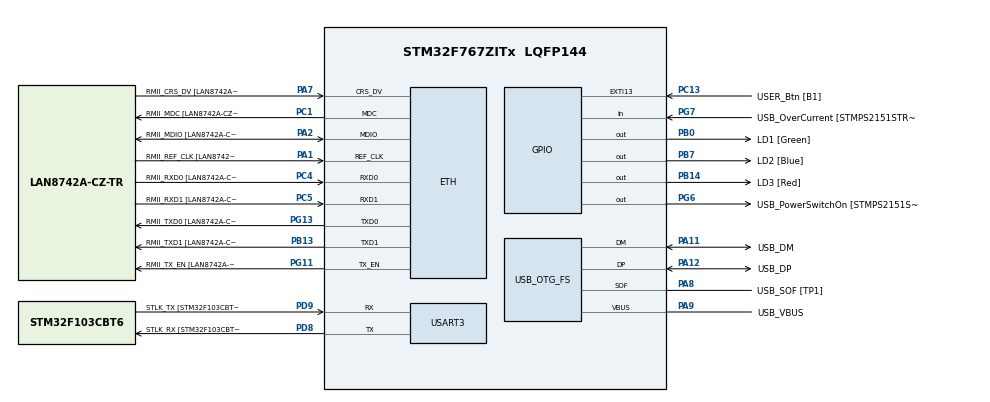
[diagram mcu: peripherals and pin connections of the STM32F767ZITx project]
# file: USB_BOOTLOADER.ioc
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ETH.MediaInterface=ETH_MEDIA_INTERFACE_RMII
ETH.PHY_Name=LAN8742A_PHY_ADDRESS
ETH.PHY_Value=0
ETH.PhyAddress=0
Mcu.Family=STM32F7
Mcu.Name=STM32F767ZITx
Mcu.Package=LQFP144
NVIC.OTG_FS_IRQn=true\:0\:0\:false\:false\:true\:true\:true
NVIC.PriorityGroup=NVIC_PRIORITYGROUP_4
PA1.GPIO_Label=RMII_REF_CLK [LAN8742A-CZ-TR_REFCLK0]
PA1.Mode=RMII
PA1.Signal=ETH_REF_CLK
PA10.GPIO_Label=USB_ID
PA10.Signal=USB_OTG_FS_ID
PA11.GPIO_Label=USB_DM
PA11.Mode=Host_Only
PA11.Signal=USB_OTG_FS_DM
PA12.GPIO_Label=USB_DP
PA12.Mode=Host_Only
PA12.Signal=USB_OTG_FS_DP
PA13.GPIO_Label=TMS
PA13.Mode=Serial_Wire
PA13.Signal=SYS_JTMS-SWDIO
PA14.GPIO_Label=TCK
PA14.Mode=Serial_Wire
PA14.Signal=SYS_JTCK-SWCLK
PA2.GPIO_Label=RMII_MDIO [LAN8742A-CZ-TR_MDIO]
PA2.Mode=RMII
PA2.Signal=ETH_MDIO
PA7.GPIO_Label=RMII_CRS_DV [LAN8742A-CZ-TR_CRS_DV]
PA7.Mode=RMII
PA7.Signal=ETH_CRS_DV
PA8.GPIO_Label=USB_SOF [TP1]
PA8.Mode=Activate_SOF_FS
PA8.Signal=USB_OTG_FS_SOF
PA9.GPIO_Label=USB_VBUS
PA9.Mode=Activate_VBUS
PA9.Signal=USB_OTG_FS_VBUS
PB0.GPIO_Label=LD1 [Green]
PB0.Signal=GPIO_Output
PB13.GPIO_Label=RMII_TXD1 [LAN8742A-CZ-TR_TXD1]
PB13.Mode=RMII
PB13.Signal=ETH_TXD1
PB14.GPIO_Label=LD3 [Red]
PB14.Signal=GPIO_Output
PB3.GPIO_Label=SWO
PB3.Signal=SYS_JTDO-SWO
PB7.GPIO_Label=LD2 [Blue]
PB7.Signal=GPIO_Output
PC1.GPIO_Label=RMII_MDC [LAN8742A-CZ-TR_MDC]
PC1.Mode=RMII
PC1.Signal=ETH_MDC
PC13.GPIO_Label=USER_Btn [B1]
PC13.Signal=GPXTI13
PC14/OSC32_IN.Mode=LSE-External-Oscillator
PC14/OSC32_IN.Signal=RCC_OSC32_IN
PC15/OSC32_OUT.Mode=LSE-External-Oscillator
PC15/OSC32_OUT.Signal=RCC_OSC32_OUT
PC4.GPIO_Label=RMII_RXD0 [LAN8742A-CZ-TR_RXD0]
PC4.Mode=RMII
PC4.Signal=ETH_RXD0
PC5.GPIO_Label=RMII_RXD1 [LAN8742A-CZ-TR_RXD1]
PC5.Mode=RMII
PC5.Signal=ETH_RXD1
PD8.GPIO_Label=STLK_RX [STM32F103CBT6_PA3]
PD8.Mode=Asynchronous
PD8.Signal=USART3_TX
PD9.GPIO_Label=STLK_TX [STM32F103CBT6_PA2]
PD9.Mode=Asynchronous
PD9.Signal=USART3_RX
PG11.GPIO_Label=RMII_TX_EN [LAN8742A-CZ-TR_TXEN]
PG11.Mode=RMII
PG11.Signal=ETH_TX_EN
PG13.GPIO_Label=RMII_TXD0 [LAN8742A-CZ-TR_TXD0]
PG13.Mode=RMII
PG13.Signal=ETH_TXD0
PG6.GPIO_Label=USB_PowerSwitchOn [STMPS2151STR_EN]
PG6.Signal=GPIO_Output
PG7.GPIO_Label=USB_OverCurrent [STMPS2151STR_FAULT]
PG7.Signal=GPIO_Input
PH0/OSC_IN.GPIO_Label=MCO [STM32F103CBT6_PA8]
PH0/OSC_IN.Mode=HSE-External-Clock-Source
PH0/OSC_IN.Signal=RCC_OSC_IN
PH1/OSC_OUT.Mode=HSE-External-Clock-Source
PH1/OSC_OUT.Signal=RCC_OSC_OUT
ProjectManager.HeapSize=0x200
ProjectManager.StackSize=0x400
ProjectManager.TargetToolchain=STM32CubeIDE
RCC.48MHZClocksFreq_Value=24000000
RCC.AHBFreq_Value=96000000
RCC.APB1CLKDivider=RCC_HCLK_DIV2
RCC.APB1Freq_Value=48000000
RCC.APB1TimFreq_Value=96000000
RCC.APB2Freq_Value=96000000
RCC.APB2TimFreq_Value=96000000
RCC.CortexFreq_Value=96000000
RCC.HCLKFreq_Value=96000000
RCC.HSE_VALUE=8000000
RCC.HSI_VALUE=16000000
RCC.PLLM=4
RCC.PLLMUL=RCC_PLL_MUL9
RCC.PLLN=96
RCC.PLLQ=4
RCC.PRESCALERUSB=RCC_USBCLKSOURCE_PLL_DIV1_5
RCC.SYSCLKFreq_VALUE=96000000
RCC.SYSCLKSource=RCC_SYSCLKSOURCE_PLLCLK
RCC.SYSCLKSourceVirtual=RCC_SYSCLKSOURCE_PLLCLK
RCC.USBFreq_Value=48000000
RCC.VCOOutputFreq_Value=192000000
USART3.VirtualMode-Asynchronous=VM_ASYNC
USB_HOST.BSP.number=1
USB_HOST.USBH_HandleTypeDef-MSC_FS=hUsbHostFS
USB_HOST.VirtualModeFS=Msc
USB_HOST0.BSP.STBoard=false
USB_HOST0.BSP.api=Unknown
USB_HOST0.BSP.i2caddr=0
USB_HOST0.BSP.instance=PG6
USB_HOST0.BSP.ip=GPIO
USB_HOST0.BSP.mode=Output
USB_HOST0.BSP.name=Drive_VBUS_FS
USB_HOST0.BSP.solution=PG6
USB_OTG_FS.VirtualMode=Host_Only
USB_OTG_FS.phy_itface=HCD_PHY_EMBEDDED
VP_FATFS_VS_USB.Mode=USB
VP_USB_HOST_VS_USB_HOST_MSC_FS.Mode=MSC_FS
board=NUCLEO-F767ZI

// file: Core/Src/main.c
/* USER CODE BEGIN Header */
/**
  ******************************************************************************
  * @file           : main.c
  * @brief          : Main program body
  ******************************************************************************
  * @attention
  *
  * <h2><center>&copy; Copyright (c) 2021 STMicroelectronics.
  * All rights reserved.</center></h2>
  *
  * This software component is licensed by ST under BSD 3-Clause license,
  * the "License"; You may not use this file except in compliance with the
  * License. You may obtain a copy of the License at:
  *                        opensource.org/licenses/BSD-3-Clause
  *
  ******************************************************************************
  */
/* USER CODE END Header */
#include "main.h"
#include "fatfs.h"
#include "usb_host.h"

/* USER CODE BEGIN Includes */
#include "flash_if.h"
#include "commands.h"
#include "log.h"
#include "Config.h"
/* USER CODE END Includes */

ETH_HandleTypeDef heth;

UART_HandleTypeDef huart3;

/* USER CODE BEGIN PV */
//typedef void (*pFunction)(void);

#ifdef __GNUC__
/* With GCC, small printf (option LD Linker->Libraries->Small printf
   set to 'Yes') calls __io_putchar() */
#define PUTCHAR_PROTOTYPE int __io_putchar(int ch)
#else
#define PUTCHAR_PROTOTYPE int fputc(int ch, FILE *f)
#endif /* __GNUC__ */

PUTCHAR_PROTOTYPE
{
  /* Place your implementation of fputc here */
  /* e.g. write a character to the USART3 and Loop until the end of transmission */
  HAL_UART_Transmit(&huart3, (uint8_t *)&ch, 1, 0xFFFF);

  return ch;
}

extern ApplicationTypeDef Appli_state;

/* USER CODE END PV */

void SystemClock_Config(void);
static void MX_GPIO_Init(void);
static void MX_ETH_Init(void);
static void MX_USART3_UART_Init(void);
void MX_USB_HOST_Process(void);

/* USER CODE BEGIN PFP */
static void USBEventHandler(void);
/* USER CODE END PFP */

int main(void)
{

	/* MCU Configuration--------------------------------------------------------*/

	/* Reset of all peripherals, Initializes the Flash interface and the Systick. */

	HAL_Init();

	/* Configure the system clock */
	SystemClock_Config();

	/* Initialize all configured peripherals */
	MX_GPIO_Init();
	MX_USART3_UART_Init();
	MX_FATFS_Init();
	MX_USB_HOST_Init();
	/* USER CODE BEGIN 2 */
	BOOT_LOG("USB BOOTLOADER..\r\n");
	printf("Please insert USB stick in 10 seconds\r\n");
	while(1)
	{
		MX_USB_HOST_Process();
		USBEventHandler();
		if(no_usb_detected())
		{
			printf("No USB stick found..");
			printf("Exiting USB BOOTLOADER\r\n");
			BootAppImage();
			printf("starting user application\r\n");
			break;
		}
	}
	/* USER CODE END 2 */

	/* Infinite loop */
	while (1)
	{
		//MX_USB_HOST_Process();

	}
}

void SystemClock_Config(void)
{
	  RCC_ClkInitTypeDef RCC_ClkInitStruct;
	  RCC_OscInitTypeDef RCC_OscInitStruct;

	  /* Enable HSE Oscillator and activate PLL with HSE as source */
	  RCC_OscInitStruct.OscillatorType = RCC_OSCILLATORTYPE_HSE;
	  RCC_OscInitStruct.HSEState = RCC_HSE_BYPASS;
	  RCC_OscInitStruct.HSIState = RCC_HSI_OFF;
	  RCC_OscInitStruct.PLL.PLLState = RCC_PLL_ON;
	  RCC_OscInitStruct.PLL.PLLSource = RCC_PLLSOURCE_HSE;
	  RCC_OscInitStruct.PLL.PLLM = 8;
	  RCC_OscInitStruct.PLL.PLLN = 432;
	  RCC_OscInitStruct.PLL.PLLP = RCC_PLLP_DIV2;
	  RCC_OscInitStruct.PLL.PLLQ = 9;
	  RCC_OscInitStruct.PLL.PLLR = 7;
	  if (HAL_RCC_OscConfig(&RCC_OscInitStruct) != HAL_OK)
	  {
	    while (1)
	    {
	    };
	  }

	  /* Activate the OverDrive to reach the 216 Mhz Frequency */
	  if (HAL_PWREx_EnableOverDrive() != HAL_OK)
	  {
	    while (1)
	    {
	    };
	  }

	  /* Select PLL as system clock source and configure the HCLK, PCLK1 and PCLK2
	   * clocks dividers */
	  RCC_ClkInitStruct.ClockType = RCC_CLOCKTYPE_SYSCLK | RCC_CLOCKTYPE_HCLK |
	                                RCC_CLOCKTYPE_PCLK1 | RCC_CLOCKTYPE_PCLK2;

	  RCC_ClkInitStruct.SYSCLKSource = RCC_SYSCLKSOURCE_PLLCLK;
	  RCC_ClkInitStruct.AHBCLKDivider = RCC_SYSCLK_DIV1;
	  RCC_ClkInitStruct.APB1CLKDivider = RCC_HCLK_DIV4;
	  RCC_ClkInitStruct.APB2CLKDivider = RCC_HCLK_DIV2;
	  if (HAL_RCC_ClockConfig(&RCC_ClkInitStruct, FLASH_LATENCY_7) != HAL_OK)
	  {
	    while (1)
	    {
	    };
	  }
}

static void MX_USART3_UART_Init(void)
{

  huart3.Instance = USART3;
  huart3.Init.BaudRate = 115200;
  huart3.Init.WordLength = UART_WORDLENGTH_8B;
  huart3.Init.StopBits = UART_STOPBITS_1;
  huart3.Init.Parity = UART_PARITY_NONE;
  huart3.Init.Mode = UART_MODE_TX_RX;
  huart3.Init.HwFlowCtl = UART_HWCONTROL_NONE;
  huart3.Init.OverSampling = UART_OVERSAMPLING_16;
  huart3.Init.OneBitSampling = UART_ONE_BIT_SAMPLE_DISABLE;
  huart3.AdvancedInit.AdvFeatureInit = UART_ADVFEATURE_NO_INIT;
  if (HAL_UART_Init(&huart3) != HAL_OK)
  {
    Error_Handler();
  }

}

static void MX_GPIO_Init(void)
{
  GPIO_InitTypeDef GPIO_InitStruct = {0};

  /* GPIO Ports Clock Enable */
  __HAL_RCC_GPIOC_CLK_ENABLE();
  __HAL_RCC_GPIOH_CLK_ENABLE();
  __HAL_RCC_GPIOA_CLK_ENABLE();
  __HAL_RCC_GPIOB_CLK_ENABLE();
  __HAL_RCC_GPIOD_CLK_ENABLE();
  __HAL_RCC_GPIOG_CLK_ENABLE();

  /*Configure GPIO pin Output Level */
  HAL_GPIO_WritePin(GPIOB, LD1_Pin|LD3_Pin|LD2_Pin, GPIO_PIN_RESET);

  /*Configure GPIO pin Output Level */
  HAL_GPIO_WritePin(USB_PowerSwitchOn_GPIO_Port, USB_PowerSwitchOn_Pin, GPIO_PIN_SET);

  /*Configure GPIO pin : USER_Btn_Pin */
  GPIO_InitStruct.Pin = USER_Btn_Pin;
  GPIO_InitStruct.Mode = GPIO_MODE_IT_RISING;
  GPIO_InitStruct.Pull = GPIO_NOPULL;
  HAL_GPIO_Init(USER_Btn_GPIO_Port, &GPIO_InitStruct);

  /*Configure GPIO pins : LD1_Pin LD3_Pin LD2_Pin */
  GPIO_InitStruct.Pin = LD1_Pin|LD3_Pin|LD2_Pin;
  GPIO_InitStruct.Mode = GPIO_MODE_OUTPUT_PP;
  GPIO_InitStruct.Pull = GPIO_NOPULL;
  GPIO_InitStruct.Speed = GPIO_SPEED_FREQ_LOW;
  HAL_GPIO_Init(GPIOB, &GPIO_InitStruct);

  /*Configure GPIO pin : USB_PowerSwitchOn_Pin */
  GPIO_InitStruct.Pin = USB_PowerSwitchOn_Pin;
  GPIO_InitStruct.Mode = GPIO_MODE_OUTPUT_PP;
  GPIO_InitStruct.Pull = GPIO_NOPULL;
  GPIO_InitStruct.Speed = GPIO_SPEED_FREQ_LOW;
  HAL_GPIO_Init(USB_PowerSwitchOn_GPIO_Port, &GPIO_InitStruct);

  /*Configure GPIO pin : USB_OverCurrent_Pin */
  GPIO_InitStruct.Pin = USB_OverCurrent_Pin;
  GPIO_InitStruct.Mode = GPIO_MODE_INPUT;
  GPIO_InitStruct.Pull = GPIO_NOPULL;
  HAL_GPIO_Init(USB_OverCurrent_GPIO_Port, &GPIO_InitStruct);

  HAL_NVIC_SetPriority(EXTI15_10_IRQn, 0, 0);
  HAL_NVIC_EnableIRQ(EXTI15_10_IRQn);
}

/* USER CODE BEGIN 4 */
/* USER CODE BEGIN 4 */
void USBEventHandler(void)
{
	switch(Appli_state)
	{
		case APPLICATION_IDLE:
			break;

		case APPLICATION_START:
			if(COMMAND_PREPARE_USB() == 0)
			{
				//Turn Green LED ON
				HAL_GPIO_WritePin(GPIOB, GPIO_PIN_0, GPIO_PIN_SET);
			}
			break;

		case APPLICATION_READY:
			BOOT_LOG("PREPARING TO DOWNLOAD APPLICATION IMAGE\r\n");
			COMMAND_DOWNLOAD();
			break;

		case APPLICATION_DISCONNECT:
			//Turn Green LED OFF
			HAL_GPIO_WritePin(GPIOB, GPIO_PIN_0, GPIO_PIN_RESET);
			break;
	}
}
/* USER CODE END 4 */

void Error_Handler(void)
{
}

/************************ (C) COPYRIGHT STMicroelectronics *****END OF FILE****/
